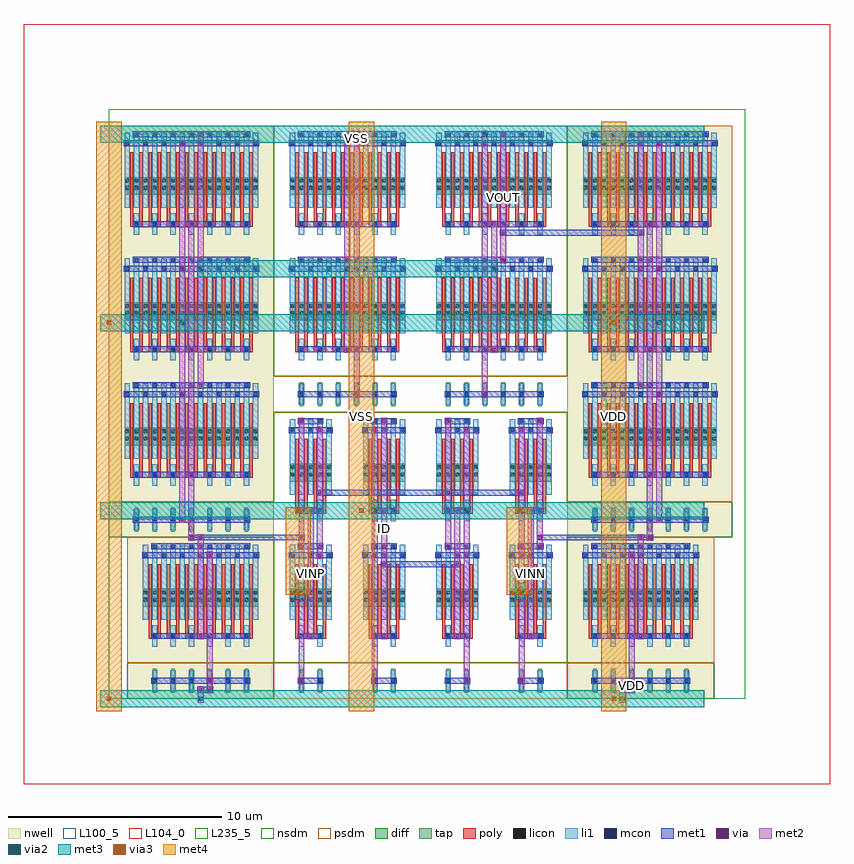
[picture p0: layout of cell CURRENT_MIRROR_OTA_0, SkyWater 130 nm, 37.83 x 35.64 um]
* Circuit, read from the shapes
.subckt CURRENT_MIRROR_OTA_0 ID VDD VINN VINP VOUT VSS
XM1 n1 VINP n2 VSS sky130_fd_pr__nfet_01v8 w=0.84 l=0.15 m=8
XM2 n3 n3 VSS VSS sky130_fd_pr__nfet_01v8 w=0.84 l=0.15 m=24
XM3 ID ID VSS VSS sky130_fd_pr__nfet_01v8 w=0.84 l=0.15 m=8
XM4 n2 ID VSS VSS sky130_fd_pr__nfet_01v8 w=0.84 l=0.15 m=8
XM5 VOUT n3 VSS VSS sky130_fd_pr__nfet_01v8 w=0.84 l=0.15 m=24
XM6 n4 VINN n2 VSS sky130_fd_pr__nfet_01v8 w=0.84 l=0.15 m=8
XM7 n3 n1 VDD VDD sky130_fd_pr__pfet_01v8 w=0.84 l=0.15 m=42
XM8 n1 n1 VDD VDD sky130_fd_pr__pfet_01v8 w=0.84 l=0.15 m=12
XM9 n4 n4 VDD VDD sky130_fd_pr__pfet_01v8 w=0.84 l=0.15 m=12
XM10 VOUT n4 VDD VDD sky130_fd_pr__pfet_01v8 w=0.84 l=0.15 m=42
.ends

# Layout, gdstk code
from math import pi, radians
import gdstk
lib = gdstk.Library(unit=1e-6, precision=1e-09)
def R(c, l, rs):  # rectangles x0, y0, x1, y1
    for r in rs: c.add(gdstk.rectangle(r[:2], r[2:], *l))
def A(c, l, x, y, w, h, nx, ny, dx, dy):  # array of equal rectangles
    R(c, l, [(x+i*dx, y+j*dy, x+i*dx+w, y+j*dy+h) for i in range(nx) for j in range(ny)])
def P(c, l, *ps):  # polygons
    for p in ps: c.add(gdstk.Polygon(p, *l))
nwell = (64, 20)
diff = (65, 20)
tap = (65, 44)
poly = (66, 20)
licon = (66, 44)
li1 = (67, 20)
mcon = (67, 44)
met1 = (68, 20)
via = (68, 44)
met2 = (69, 20)
via2 = (69, 44)
met3 = (70, 20)
via3 = (70, 44)
met4 = (71, 20)
nsdm = (93, 44)
psdm = (94, 20)
L100_5 = (100, 5)
L104_0 = (104, 0)
L235_5 = (235, 5)

dcl_nmos_s_47956387_x2_y = lib.new_cell('DCL_NMOS_S_47956387_X2_Y2_1725381638')
R(dcl_nmos_s_47956387_x2_y, diff, [(0.735,2.415,2.705,3.255), (0.735,8.295,2.705,9.135)])
R(dcl_nmos_s_47956387_x2_y, tap, [(1.205,12.04,1.375,13.16), (2.065,12.04,2.235,13.16)])
A(dcl_nmos_s_47956387_x2_y, poly, 1, 1.26, 0.15, 3.36, 4, 2, 0.43, 5.88)
R(dcl_nmos_s_47956387_x2_y, poly, [(1,4.485,1.58,4.755), (1.86,4.485,2.44,4.755), (1,10.365,1.58,10.635), (1.86,10.365,2.44,10.635)])
A(dcl_nmos_s_47956387_x2_y, licon, 0.775, 2.495, 0.17, 0.17, 3, 2, 0.43, 0.34)
A(dcl_nmos_s_47956387_x2_y, licon, 1.635, 2.495, 0.17, 0.17, 3, 2, 0.43, 0.34)
A(dcl_nmos_s_47956387_x2_y, licon, 0.775, 8.375, 0.17, 0.17, 3, 2, 0.43, 0.34)
A(dcl_nmos_s_47956387_x2_y, licon, 1.635, 8.375, 0.17, 0.17, 3, 2, 0.43, 0.34)
R(dcl_nmos_s_47956387_x2_y, licon, [(1.205,4.535,1.375,4.705), (2.065,4.535,2.235,4.705), (1.205,10.415,1.375,10.585), (2.065,10.415,2.235,10.585), (1.205,12.515,1.375,12.685), (1.205,12.515,1.375,12.685), (2.065,12.515,2.235,12.685), (2.065,12.515,2.235,12.685)])
A(dcl_nmos_s_47956387_x2_y, li1, 0.735, 0.335, 0.25, 3.53, 5, 2, 0.43, 5.88)
R(dcl_nmos_s_47956387_x2_y, li1, [(1.165,4.115,1.415,5.125), (2.025,4.115,2.275,5.125), (1.165,9.995,1.415,11.005), (2.025,9.995,2.275,11.005), (1.165,12.095,1.415,13.105), (2.025,12.095,2.275,13.105)])
A(dcl_nmos_s_47956387_x2_y, mcon, 0.775, 0.755, 0.17, 0.17, 3, 2, 0.86, 5.88)
R(dcl_nmos_s_47956387_x2_y, mcon, [(1.205,0.335,1.375,0.505), (2.065,0.335,2.235,0.505), (1.205,4.535,1.375,4.705), (2.065,4.535,2.235,4.705), (1.205,6.215,1.375,6.385), (2.065,6.215,2.235,6.385), (1.205,10.415,1.375,10.585), (2.065,10.415,2.235,10.585), (1.205,12.515,1.375,12.685), (2.065,12.515,2.235,12.685)])
R(dcl_nmos_s_47956387_x2_y, met1, [(1.12,0.28,2.32,0.56), (0.69,0.7,2.75,0.98), (1.12,4.48,2.32,4.76), (1.12,6.16,2.32,6.44), (0.69,6.58,2.75,6.86), (1.12,10.36,2.32,10.64), (1.12,12.46,2.32,12.74)])
A(dcl_nmos_s_47956387_x2_y, via, 2.075, 0.765, 0.15, 0.15, 1, 3, 0, 5.88)
R(dcl_nmos_s_47956387_x2_y, via, [(1.645,0.345,1.795,0.495), (1.645,4.545,1.795,4.695), (1.645,6.225,1.795,6.375), (1.645,10.425,1.795,10.575)])
R(dcl_nmos_s_47956387_x2_y, met2, [(1.58,0.26,1.86,10.66), (2.01,0.68,2.29,12.76)])
R(dcl_nmos_s_47956387_x2_y, nsdm, [(0,0,3.44,11.76)])
R(dcl_nmos_s_47956387_x2_y, psdm, [(0,11.76,3.44,13.44)])
R(dcl_nmos_s_47956387_x2_y, L100_5, [(0,0,3.44,13.44)])

dcl_nmos_s_13341824_x6_y = lib.new_cell('DCL_NMOS_S_13341824_X6_Y2_1725381637')
R(dcl_nmos_s_13341824_x6_y, diff, [(0.735,2.415,6.145,3.255), (0.735,8.295,6.145,9.135)])
A(dcl_nmos_s_13341824_x6_y, tap, 1.205, 12.04, 0.17, 1.12, 6, 1, 0.86, 0)
A(dcl_nmos_s_13341824_x6_y, poly, 1, 1.26, 0.15, 3.36, 12, 2, 0.43, 5.88)
A(dcl_nmos_s_13341824_x6_y, poly, 1, 4.485, 0.58, 0.27, 6, 2, 0.86, 5.88)
A(dcl_nmos_s_13341824_x6_y, licon, 0.775, 2.495, 0.17, 0.17, 3, 2, 0.43, 0.34)
A(dcl_nmos_s_13341824_x6_y, licon, 1.635, 2.495, 0.17, 0.17, 3, 2, 0.43, 0.34)
A(dcl_nmos_s_13341824_x6_y, licon, 2.495, 2.495, 0.17, 0.17, 3, 2, 0.43, 0.34)
A(dcl_nmos_s_13341824_x6_y, licon, 3.355, 2.495, 0.17, 0.17, 3, 2, 0.43, 0.34)
A(dcl_nmos_s_13341824_x6_y, licon, 4.215, 2.495, 0.17, 0.17, 3, 2, 0.43, 0.34)
A(dcl_nmos_s_13341824_x6_y, licon, 5.075, 2.495, 0.17, 0.17, 3, 2, 0.43, 0.34)
A(dcl_nmos_s_13341824_x6_y, licon, 1.205, 4.535, 0.17, 0.17, 6, 2, 0.86, 5.88)
A(dcl_nmos_s_13341824_x6_y, licon, 0.775, 8.375, 0.17, 0.17, 3, 2, 0.43, 0.34)
A(dcl_nmos_s_13341824_x6_y, licon, 1.635, 8.375, 0.17, 0.17, 3, 2, 0.43, 0.34)
A(dcl_nmos_s_13341824_x6_y, licon, 2.495, 8.375, 0.17, 0.17, 3, 2, 0.43, 0.34)
A(dcl_nmos_s_13341824_x6_y, licon, 3.355, 8.375, 0.17, 0.17, 3, 2, 0.43, 0.34)
A(dcl_nmos_s_13341824_x6_y, licon, 4.215, 8.375, 0.17, 0.17, 3, 2, 0.43, 0.34)
A(dcl_nmos_s_13341824_x6_y, licon, 5.075, 8.375, 0.17, 0.17, 3, 2, 0.43, 0.34)
R(dcl_nmos_s_13341824_x6_y, licon, [(1.205,12.515,1.375,12.685), (1.205,12.515,1.375,12.685), (2.065,12.515,2.235,12.685), (2.065,12.515,2.235,12.685), (2.925,12.515,3.095,12.685), (2.925,12.515,3.095,12.685), (3.785,12.515,3.955,12.685), (3.785,12.515,3.955,12.685), (4.645,12.515,4.815,12.685), (4.645,12.515,4.815,12.685), (5.505,12.515,5.675,12.685), (5.505,12.515,5.675,12.685)])
A(dcl_nmos_s_13341824_x6_y, li1, 0.735, 0.335, 0.25, 3.53, 13, 2, 0.43, 5.88)
A(dcl_nmos_s_13341824_x6_y, li1, 1.165, 4.115, 0.25, 1.01, 6, 2, 0.86, 5.88)
A(dcl_nmos_s_13341824_x6_y, li1, 1.165, 12.095, 0.25, 1.01, 6, 1, 0.86, 0)
A(dcl_nmos_s_13341824_x6_y, mcon, 1.205, 0.335, 0.17, 0.17, 6, 2, 0.86, 4.2)
A(dcl_nmos_s_13341824_x6_y, mcon, 0.775, 0.755, 0.17, 0.17, 7, 2, 0.86, 5.88)
A(dcl_nmos_s_13341824_x6_y, mcon, 1.205, 6.215, 0.17, 0.17, 6, 2, 0.86, 4.2)
A(dcl_nmos_s_13341824_x6_y, mcon, 1.205, 12.515, 0.17, 0.17, 6, 1, 0.86, 0)
R(dcl_nmos_s_13341824_x6_y, met1, [(1.12,0.28,5.76,0.56), (0.69,0.7,6.19,0.98), (1.12,4.48,5.76,4.76), (1.12,6.16,5.76,6.44), (0.69,6.58,6.19,6.86), (1.12,10.36,5.76,10.64), (1.12,12.46,5.76,12.74)])
A(dcl_nmos_s_13341824_x6_y, via, 3.795, 0.765, 0.15, 0.15, 1, 3, 0, 5.88)
R(dcl_nmos_s_13341824_x6_y, via, [(3.365,0.345,3.515,0.495), (3.365,4.545,3.515,4.695), (3.365,6.225,3.515,6.375), (3.365,10.425,3.515,10.575)])
R(dcl_nmos_s_13341824_x6_y, met2, [(3.3,0.26,3.58,10.66), (3.73,0.68,4.01,12.76)])
R(dcl_nmos_s_13341824_x6_y, nsdm, [(0,0,6.88,11.76)])
R(dcl_nmos_s_13341824_x6_y, psdm, [(0,11.76,6.88,13.44)])
R(dcl_nmos_s_13341824_x6_y, L100_5, [(0,0,6.88,13.44)])

dcl_pmos_s_40212493_x6_y = lib.new_cell('DCL_PMOS_S_40212493_X6_Y1_1725381639')
R(dcl_pmos_s_40212493_x6_y, nwell, [(0,0,6.88,7.56)])
R(dcl_pmos_s_40212493_x6_y, diff, [(0.735,2.415,6.145,3.255)])
A(dcl_pmos_s_40212493_x6_y, tap, 1.205, 6.16, 0.17, 1.12, 6, 1, 0.86, 0)
A(dcl_pmos_s_40212493_x6_y, poly, 1, 1.26, 0.15, 3.36, 12, 1, 0.43, 0)
A(dcl_pmos_s_40212493_x6_y, poly, 1, 4.485, 0.58, 0.27, 6, 1, 0.86, 0)
A(dcl_pmos_s_40212493_x6_y, licon, 0.775, 2.495, 0.17, 0.17, 3, 2, 0.43, 0.34)
A(dcl_pmos_s_40212493_x6_y, licon, 1.635, 2.495, 0.17, 0.17, 3, 2, 0.43, 0.34)
A(dcl_pmos_s_40212493_x6_y, licon, 2.495, 2.495, 0.17, 0.17, 3, 2, 0.43, 0.34)
A(dcl_pmos_s_40212493_x6_y, licon, 3.355, 2.495, 0.17, 0.17, 3, 2, 0.43, 0.34)
A(dcl_pmos_s_40212493_x6_y, licon, 4.215, 2.495, 0.17, 0.17, 3, 2, 0.43, 0.34)
A(dcl_pmos_s_40212493_x6_y, licon, 5.075, 2.495, 0.17, 0.17, 3, 2, 0.43, 0.34)
A(dcl_pmos_s_40212493_x6_y, licon, 1.205, 4.535, 0.17, 0.17, 6, 2, 0.86, 2.1)
A(dcl_pmos_s_40212493_x6_y, li1, 0.735, 0.335, 0.25, 3.53, 13, 1, 0.43, 0)
A(dcl_pmos_s_40212493_x6_y, li1, 1.165, 4.115, 0.25, 1.01, 6, 2, 0.86, 2.1)
A(dcl_pmos_s_40212493_x6_y, mcon, 1.205, 0.335, 0.17, 0.17, 6, 2, 0.86, 4.2)
A(dcl_pmos_s_40212493_x6_y, mcon, 0.775, 0.755, 0.17, 0.17, 7, 1, 0.86, 0)
A(dcl_pmos_s_40212493_x6_y, mcon, 1.205, 6.635, 0.17, 0.17, 6, 1, 0.86, 0)
R(dcl_pmos_s_40212493_x6_y, met1, [(1.12,0.28,5.76,0.56), (0.69,0.7,6.19,0.98), (1.12,4.48,5.76,4.76), (1.12,6.58,5.76,6.86)])
R(dcl_pmos_s_40212493_x6_y, via, [(3.365,0.345,3.515,0.495), (3.795,0.765,3.945,0.915), (3.365,4.545,3.515,4.695), (3.795,6.645,3.945,6.795)])
R(dcl_pmos_s_40212493_x6_y, met2, [(3.3,0.26,3.58,4.78), (3.73,0.68,4.01,6.88)])
R(dcl_pmos_s_40212493_x6_y, nsdm, [(0,5.88,6.88,7.56)])
R(dcl_pmos_s_40212493_x6_y, psdm, [(0,0,6.88,5.88)])
R(dcl_pmos_s_40212493_x6_y, L100_5, [(0,0,6.88,7.56)])

nmos_s_7151189_x6_y2_172 = lib.new_cell('NMOS_S_7151189_X6_Y2_1725381642')
R(nmos_s_7151189_x6_y2_172, diff, [(0.735,2.415,6.145,3.255), (0.735,8.295,6.145,9.135)])
A(nmos_s_7151189_x6_y2_172, tap, 1.205, 12.04, 0.17, 1.12, 6, 1, 0.86, 0)
A(nmos_s_7151189_x6_y2_172, poly, 1, 1.26, 0.15, 3.36, 12, 2, 0.43, 5.88)
A(nmos_s_7151189_x6_y2_172, poly, 1, 4.485, 0.58, 0.27, 6, 2, 0.86, 5.88)
A(nmos_s_7151189_x6_y2_172, licon, 0.775, 2.495, 0.17, 0.17, 3, 2, 0.43, 0.34)
A(nmos_s_7151189_x6_y2_172, licon, 1.635, 2.495, 0.17, 0.17, 3, 2, 0.43, 0.34)
A(nmos_s_7151189_x6_y2_172, licon, 2.495, 2.495, 0.17, 0.17, 3, 2, 0.43, 0.34)
A(nmos_s_7151189_x6_y2_172, licon, 3.355, 2.495, 0.17, 0.17, 3, 2, 0.43, 0.34)
A(nmos_s_7151189_x6_y2_172, licon, 4.215, 2.495, 0.17, 0.17, 3, 2, 0.43, 0.34)
A(nmos_s_7151189_x6_y2_172, licon, 5.075, 2.495, 0.17, 0.17, 3, 2, 0.43, 0.34)
A(nmos_s_7151189_x6_y2_172, licon, 1.205, 4.535, 0.17, 0.17, 6, 2, 0.86, 5.88)
A(nmos_s_7151189_x6_y2_172, licon, 0.775, 8.375, 0.17, 0.17, 3, 2, 0.43, 0.34)
A(nmos_s_7151189_x6_y2_172, licon, 1.635, 8.375, 0.17, 0.17, 3, 2, 0.43, 0.34)
A(nmos_s_7151189_x6_y2_172, licon, 2.495, 8.375, 0.17, 0.17, 3, 2, 0.43, 0.34)
A(nmos_s_7151189_x6_y2_172, licon, 3.355, 8.375, 0.17, 0.17, 3, 2, 0.43, 0.34)
A(nmos_s_7151189_x6_y2_172, licon, 4.215, 8.375, 0.17, 0.17, 3, 2, 0.43, 0.34)
A(nmos_s_7151189_x6_y2_172, licon, 5.075, 8.375, 0.17, 0.17, 3, 2, 0.43, 0.34)
R(nmos_s_7151189_x6_y2_172, licon, [(1.205,12.515,1.375,12.685), (1.205,12.515,1.375,12.685), (2.065,12.515,2.235,12.685), (2.065,12.515,2.235,12.685), (2.925,12.515,3.095,12.685), (2.925,12.515,3.095,12.685), (3.785,12.515,3.955,12.685), (3.785,12.515,3.955,12.685), (4.645,12.515,4.815,12.685), (4.645,12.515,4.815,12.685), (5.505,12.515,5.675,12.685), (5.505,12.515,5.675,12.685)])
A(nmos_s_7151189_x6_y2_172, li1, 0.735, 0.335, 0.25, 3.53, 13, 2, 0.43, 5.88)
A(nmos_s_7151189_x6_y2_172, li1, 1.165, 4.115, 0.25, 1.01, 6, 2, 0.86, 5.88)
A(nmos_s_7151189_x6_y2_172, li1, 1.165, 12.095, 0.25, 1.01, 6, 1, 0.86, 0)
A(nmos_s_7151189_x6_y2_172, mcon, 1.205, 0.335, 0.17, 0.17, 6, 2, 0.86, 4.2)
A(nmos_s_7151189_x6_y2_172, mcon, 0.775, 0.755, 0.17, 0.17, 7, 2, 0.86, 5.88)
A(nmos_s_7151189_x6_y2_172, mcon, 1.205, 6.215, 0.17, 0.17, 6, 2, 0.86, 4.2)
A(nmos_s_7151189_x6_y2_172, mcon, 1.205, 12.515, 0.17, 0.17, 6, 1, 0.86, 0)
R(nmos_s_7151189_x6_y2_172, met1, [(1.12,0.28,5.76,0.56), (0.69,0.7,6.19,0.98), (1.12,4.48,5.76,4.76), (1.12,6.16,5.76,6.44), (0.69,6.58,6.19,6.86), (1.12,10.36,5.76,10.64), (1.12,12.46,5.76,12.74)])
A(nmos_s_7151189_x6_y2_172, via, 3.795, 0.765, 0.15, 0.15, 1, 3, 0, 5.88)
R(nmos_s_7151189_x6_y2_172, via, [(2.935,0.345,3.085,0.495), (3.365,4.545,3.515,4.695), (2.935,6.225,3.085,6.375), (3.365,10.425,3.515,10.575)])
R(nmos_s_7151189_x6_y2_172, met2, [(2.87,0.26,3.15,6.46), (3.73,0.68,4.01,12.76), (3.3,4.46,3.58,10.66)])
R(nmos_s_7151189_x6_y2_172, nsdm, [(0,0,6.88,11.76)])
R(nmos_s_7151189_x6_y2_172, psdm, [(0,11.76,6.88,13.44)])
R(nmos_s_7151189_x6_y2_172, L100_5, [(0,0,6.88,13.44)])

nmos_s_18635307_x2_y2_17 = lib.new_cell('NMOS_S_18635307_X2_Y2_1725381641')
R(nmos_s_18635307_x2_y2_17, diff, [(0.735,2.415,2.705,3.255), (0.735,8.295,2.705,9.135)])
R(nmos_s_18635307_x2_y2_17, tap, [(1.205,12.04,1.375,13.16), (2.065,12.04,2.235,13.16)])
A(nmos_s_18635307_x2_y2_17, poly, 1, 1.26, 0.15, 3.36, 4, 2, 0.43, 5.88)
R(nmos_s_18635307_x2_y2_17, poly, [(1,4.485,1.58,4.755), (1.86,4.485,2.44,4.755), (1,10.365,1.58,10.635), (1.86,10.365,2.44,10.635)])
A(nmos_s_18635307_x2_y2_17, licon, 0.775, 2.495, 0.17, 0.17, 3, 2, 0.43, 0.34)
A(nmos_s_18635307_x2_y2_17, licon, 1.635, 2.495, 0.17, 0.17, 3, 2, 0.43, 0.34)
A(nmos_s_18635307_x2_y2_17, licon, 0.775, 8.375, 0.17, 0.17, 3, 2, 0.43, 0.34)
A(nmos_s_18635307_x2_y2_17, licon, 1.635, 8.375, 0.17, 0.17, 3, 2, 0.43, 0.34)
R(nmos_s_18635307_x2_y2_17, licon, [(1.205,4.535,1.375,4.705), (2.065,4.535,2.235,4.705), (1.205,10.415,1.375,10.585), (2.065,10.415,2.235,10.585), (1.205,12.515,1.375,12.685), (1.205,12.515,1.375,12.685), (2.065,12.515,2.235,12.685), (2.065,12.515,2.235,12.685)])
A(nmos_s_18635307_x2_y2_17, li1, 0.735, 0.335, 0.25, 3.53, 5, 2, 0.43, 5.88)
R(nmos_s_18635307_x2_y2_17, li1, [(1.165,4.115,1.415,5.125), (2.025,4.115,2.275,5.125), (1.165,9.995,1.415,11.005), (2.025,9.995,2.275,11.005), (1.165,12.095,1.415,13.105), (2.025,12.095,2.275,13.105)])
A(nmos_s_18635307_x2_y2_17, mcon, 0.775, 0.755, 0.17, 0.17, 3, 2, 0.86, 5.88)
R(nmos_s_18635307_x2_y2_17, mcon, [(1.205,0.335,1.375,0.505), (2.065,0.335,2.235,0.505), (1.205,4.535,1.375,4.705), (2.065,4.535,2.235,4.705), (1.205,6.215,1.375,6.385), (2.065,6.215,2.235,6.385), (1.205,10.415,1.375,10.585), (2.065,10.415,2.235,10.585), (1.205,12.515,1.375,12.685), (2.065,12.515,2.235,12.685)])
R(nmos_s_18635307_x2_y2_17, met1, [(1.12,0.28,2.32,0.56), (0.69,0.7,2.75,0.98), (1.12,4.48,2.32,4.76), (1.12,6.16,2.32,6.44), (0.69,6.58,2.75,6.86), (1.12,10.36,2.32,10.64), (1.12,12.46,2.32,12.74)])
A(nmos_s_18635307_x2_y2_17, via, 2.075, 0.765, 0.15, 0.15, 1, 3, 0, 5.88)
R(nmos_s_18635307_x2_y2_17, via, [(1.215,0.345,1.365,0.495), (1.645,4.545,1.795,4.695), (1.215,6.225,1.365,6.375), (1.645,10.425,1.795,10.575)])
R(nmos_s_18635307_x2_y2_17, met2, [(1.15,0.26,1.43,6.46), (2.01,0.68,2.29,12.76), (1.58,4.46,1.86,10.66)])
R(nmos_s_18635307_x2_y2_17, nsdm, [(0,0,3.44,11.76)])
R(nmos_s_18635307_x2_y2_17, psdm, [(0,11.76,3.44,13.44)])
R(nmos_s_18635307_x2_y2_17, L100_5, [(0,0,3.44,13.44)])

pmos_s_18257507_x7_y3_17 = lib.new_cell('PMOS_S_18257507_X7_Y3_1725381643')
R(pmos_s_18257507_x7_y3_17, nwell, [(0,0,7.74,19.32)])
A(pmos_s_18257507_x7_y3_17, diff, 0.735, 2.415, 6.27, 0.84, 1, 3, 0, 5.88)
A(pmos_s_18257507_x7_y3_17, tap, 1.205, 17.92, 0.17, 1.12, 7, 1, 0.86, 0)
A(pmos_s_18257507_x7_y3_17, poly, 1, 1.26, 0.15, 3.36, 14, 3, 0.43, 5.88)
A(pmos_s_18257507_x7_y3_17, poly, 1, 4.485, 0.58, 0.27, 7, 3, 0.86, 5.88)
A(pmos_s_18257507_x7_y3_17, licon, 0.775, 2.495, 0.17, 0.17, 3, 2, 0.43, 0.34)
A(pmos_s_18257507_x7_y3_17, licon, 1.635, 2.495, 0.17, 0.17, 3, 2, 0.43, 0.34)
A(pmos_s_18257507_x7_y3_17, licon, 2.495, 2.495, 0.17, 0.17, 3, 2, 0.43, 0.34)
A(pmos_s_18257507_x7_y3_17, licon, 3.355, 2.495, 0.17, 0.17, 3, 2, 0.43, 0.34)
A(pmos_s_18257507_x7_y3_17, licon, 4.215, 2.495, 0.17, 0.17, 3, 2, 0.43, 0.34)
A(pmos_s_18257507_x7_y3_17, licon, 5.075, 2.495, 0.17, 0.17, 3, 2, 0.43, 0.34)
A(pmos_s_18257507_x7_y3_17, licon, 5.935, 2.495, 0.17, 0.17, 3, 2, 0.43, 0.34)
A(pmos_s_18257507_x7_y3_17, licon, 1.205, 4.535, 0.17, 0.17, 7, 3, 0.86, 5.88)
A(pmos_s_18257507_x7_y3_17, licon, 0.775, 8.375, 0.17, 0.17, 3, 2, 0.43, 0.34)
A(pmos_s_18257507_x7_y3_17, licon, 1.635, 8.375, 0.17, 0.17, 3, 2, 0.43, 0.34)
A(pmos_s_18257507_x7_y3_17, licon, 2.495, 8.375, 0.17, 0.17, 3, 2, 0.43, 0.34)
A(pmos_s_18257507_x7_y3_17, licon, 3.355, 8.375, 0.17, 0.17, 3, 2, 0.43, 0.34)
A(pmos_s_18257507_x7_y3_17, licon, 4.215, 8.375, 0.17, 0.17, 3, 2, 0.43, 0.34)
A(pmos_s_18257507_x7_y3_17, licon, 5.075, 8.375, 0.17, 0.17, 3, 2, 0.43, 0.34)
A(pmos_s_18257507_x7_y3_17, licon, 5.935, 8.375, 0.17, 0.17, 3, 2, 0.43, 0.34)
A(pmos_s_18257507_x7_y3_17, licon, 0.775, 14.255, 0.17, 0.17, 3, 2, 0.43, 0.34)
A(pmos_s_18257507_x7_y3_17, licon, 1.635, 14.255, 0.17, 0.17, 3, 2, 0.43, 0.34)
A(pmos_s_18257507_x7_y3_17, licon, 2.495, 14.255, 0.17, 0.17, 3, 2, 0.43, 0.34)
A(pmos_s_18257507_x7_y3_17, licon, 3.355, 14.255, 0.17, 0.17, 3, 2, 0.43, 0.34)
A(pmos_s_18257507_x7_y3_17, licon, 4.215, 14.255, 0.17, 0.17, 3, 2, 0.43, 0.34)
A(pmos_s_18257507_x7_y3_17, licon, 5.075, 14.255, 0.17, 0.17, 3, 2, 0.43, 0.34)
A(pmos_s_18257507_x7_y3_17, licon, 5.935, 14.255, 0.17, 0.17, 3, 2, 0.43, 0.34)
R(pmos_s_18257507_x7_y3_17, licon, [(1.205,18.395,1.375,18.565), (1.205,18.395,1.375,18.565), (1.205,18.395,1.375,18.565), (2.065,18.395,2.235,18.565), (2.065,18.395,2.235,18.565), (2.065,18.395,2.235,18.565), (2.925,18.395,3.095,18.565), (2.925,18.395,3.095,18.565), (2.925,18.395,3.095,18.565), (3.785,18.395,3.955,18.565), (3.785,18.395,3.955,18.565), (3.785,18.395,3.955,18.565), (4.645,18.395,4.815,18.565), (4.645,18.395,4.815,18.565), (4.645,18.395,4.815,18.565), (5.505,18.395,5.675,18.565), (5.505,18.395,5.675,18.565), (5.505,18.395,5.675,18.565), (6.365,18.395,6.535,18.565), (6.365,18.395,6.535,18.565), (6.365,18.395,6.535,18.565)])
A(pmos_s_18257507_x7_y3_17, li1, 0.735, 0.335, 0.25, 3.53, 15, 3, 0.43, 5.88)
A(pmos_s_18257507_x7_y3_17, li1, 1.165, 4.115, 0.25, 1.01, 7, 3, 0.86, 5.88)
A(pmos_s_18257507_x7_y3_17, li1, 1.165, 17.975, 0.25, 1.01, 7, 1, 0.86, 0)
A(pmos_s_18257507_x7_y3_17, mcon, 1.205, 0.335, 0.17, 0.17, 7, 2, 0.86, 4.2)
A(pmos_s_18257507_x7_y3_17, mcon, 0.775, 0.755, 0.17, 0.17, 8, 3, 0.86, 5.88)
A(pmos_s_18257507_x7_y3_17, mcon, 1.205, 6.215, 0.17, 0.17, 7, 2, 0.86, 4.2)
A(pmos_s_18257507_x7_y3_17, mcon, 1.205, 12.095, 0.17, 0.17, 7, 2, 0.86, 4.2)
A(pmos_s_18257507_x7_y3_17, mcon, 1.205, 18.395, 0.17, 0.17, 7, 1, 0.86, 0)
A(pmos_s_18257507_x7_y3_17, met1, 0.69, 0.7, 6.36, 0.28, 1, 3, 0, 5.88)
R(pmos_s_18257507_x7_y3_17, met1, [(1.12,0.28,6.62,0.56), (1.12,4.48,6.62,4.76), (1.12,6.16,6.62,6.44), (1.12,10.36,6.62,10.64), (1.12,12.04,6.62,12.32), (1.12,16.24,6.62,16.52), (1.12,18.34,6.62,18.62)])
A(pmos_s_18257507_x7_y3_17, via, 3.365, 0.345, 0.15, 0.15, 1, 3, 0, 5.88)
A(pmos_s_18257507_x7_y3_17, via, 4.225, 0.765, 0.15, 0.15, 1, 4, 0, 5.88)
A(pmos_s_18257507_x7_y3_17, via, 3.795, 4.545, 0.15, 0.15, 1, 3, 0, 5.88)
R(pmos_s_18257507_x7_y3_17, met2, [(3.3,0.26,3.58,12.34), (4.16,0.68,4.44,18.64), (3.73,4.46,4.01,16.54)])
R(pmos_s_18257507_x7_y3_17, nsdm, [(0,17.64,7.74,19.32)])
R(pmos_s_18257507_x7_y3_17, psdm, [(0,0,7.74,17.64)])
R(pmos_s_18257507_x7_y3_17, L100_5, [(0,0,7.74,19.32)])

nmos_4t_40251920_x2_y2_1 = lib.new_cell('NMOS_4T_40251920_X2_Y2_1725381640')
R(nmos_4t_40251920_x2_y2_1, diff, [(0.735,2.415,2.705,3.255), (0.735,8.295,2.705,9.135)])
R(nmos_4t_40251920_x2_y2_1, tap, [(1.205,12.04,1.375,13.16), (2.065,12.04,2.235,13.16)])
A(nmos_4t_40251920_x2_y2_1, poly, 1, 1.26, 0.15, 3.36, 4, 2, 0.43, 5.88)
R(nmos_4t_40251920_x2_y2_1, poly, [(1,4.485,1.58,4.755), (1.86,4.485,2.44,4.755), (1,10.365,1.58,10.635), (1.86,10.365,2.44,10.635)])
A(nmos_4t_40251920_x2_y2_1, licon, 0.775, 2.495, 0.17, 0.17, 3, 2, 0.43, 0.34)
A(nmos_4t_40251920_x2_y2_1, licon, 1.635, 2.495, 0.17, 0.17, 3, 2, 0.43, 0.34)
A(nmos_4t_40251920_x2_y2_1, licon, 0.775, 8.375, 0.17, 0.17, 3, 2, 0.43, 0.34)
A(nmos_4t_40251920_x2_y2_1, licon, 1.635, 8.375, 0.17, 0.17, 3, 2, 0.43, 0.34)
R(nmos_4t_40251920_x2_y2_1, licon, [(1.205,4.535,1.375,4.705), (2.065,4.535,2.235,4.705), (1.205,10.415,1.375,10.585), (2.065,10.415,2.235,10.585), (1.205,12.515,1.375,12.685), (1.205,12.515,1.375,12.685), (2.065,12.515,2.235,12.685), (2.065,12.515,2.235,12.685)])
A(nmos_4t_40251920_x2_y2_1, li1, 0.735, 0.335, 0.25, 3.53, 5, 2, 0.43, 5.88)
R(nmos_4t_40251920_x2_y2_1, li1, [(1.165,4.115,1.415,5.125), (2.025,4.115,2.275,5.125), (1.165,9.995,1.415,11.005), (2.025,9.995,2.275,11.005), (1.165,12.095,1.415,13.105), (2.025,12.095,2.275,13.105)])
A(nmos_4t_40251920_x2_y2_1, mcon, 0.775, 0.755, 0.17, 0.17, 3, 2, 0.86, 5.88)
R(nmos_4t_40251920_x2_y2_1, mcon, [(1.205,0.335,1.375,0.505), (2.065,0.335,2.235,0.505), (1.205,4.535,1.375,4.705), (2.065,4.535,2.235,4.705), (1.205,6.215,1.375,6.385), (2.065,6.215,2.235,6.385), (1.205,10.415,1.375,10.585), (2.065,10.415,2.235,10.585), (1.205,12.515,1.375,12.685), (2.065,12.515,2.235,12.685)])
R(nmos_4t_40251920_x2_y2_1, met1, [(1.12,0.28,2.32,0.56), (0.69,0.7,2.75,0.98), (1.12,4.48,2.32,4.76), (1.12,6.16,2.32,6.44), (0.69,6.58,2.75,6.86), (1.12,10.36,2.32,10.64), (1.12,12.46,2.32,12.74)])
R(nmos_4t_40251920_x2_y2_1, via, [(1.215,0.345,1.365,0.495), (2.075,0.765,2.225,0.915), (1.645,4.545,1.795,4.695), (1.215,6.225,1.365,6.375), (2.075,6.645,2.225,6.795), (1.645,10.425,1.795,10.575)])
R(nmos_4t_40251920_x2_y2_1, met2, [(1.15,0.26,1.43,6.46), (2.01,0.68,2.29,6.88), (1.58,4.46,1.86,10.66)])
R(nmos_4t_40251920_x2_y2_1, nsdm, [(0,0,3.44,11.76)])
R(nmos_4t_40251920_x2_y2_1, psdm, [(0,11.76,3.44,13.44)])
R(nmos_4t_40251920_x2_y2_1, L100_5, [(0,0,3.44,13.44)])

current_mirror_ota_0 = lib.new_cell('CURRENT_MIRROR_OTA_0')
R(current_mirror_ota_0, met1, [(4.14,0.28,4.46,0.56), (4.14,0.28,4.46,0.56), (4.14,0.28,4.46,0.56), (4.14,0.28,4.46,0.56), (4.3,0.28,4.73,0.56), (4.57,0.28,4.89,0.56), (4.57,0.28,4.89,0.56), (4.57,0.28,4.89,0.56), (4.57,0.28,4.89,0.56), (23.92,0.28,24.24,0.56), (23.92,0.28,24.24,0.56), (23.92,0.28,24.24,0.56), (23.92,0.28,24.24,0.56), (23.92,0.28,24.24,0.56), (24.08,0.28,24.51,0.56), (24.35,0.28,24.67,0.56), (24.35,0.28,24.67,0.56), (24.35,0.28,24.67,0.56), (24.35,0.28,24.67,0.56), (24.35,0.28,24.67,0.56), (8.87,0.7,9.19,0.98), (8.87,0.7,9.19,0.98), (19.19,0.7,19.51,0.98), (19.19,0.7,19.51,0.98), (19.19,0.7,19.51,0.98), (12.74,6.16,13.06,6.44), (12.74,6.16,13.06,6.44), (12.9,6.16,16.34,6.44), (16.18,6.16,16.5,6.44), (16.18,6.16,16.5,6.44), (3.71,7.42,4.03,7.7), (3.71,7.42,4.03,7.7), (3.87,7.42,4.3,7.7), (4.14,7.42,4.46,7.7), (4.14,7.42,4.46,7.7), (4.14,7.42,4.46,7.7), (4.14,7.42,4.46,7.7), (4.3,7.42,9.03,7.7), (8.87,7.42,9.19,7.7), (8.87,7.42,9.19,7.7), (8.87,7.42,9.19,7.7), (8.87,7.42,9.19,7.7), (20.05,7.42,20.37,7.7), (20.05,7.42,20.37,7.7), (20.05,7.42,20.37,7.7), (20.05,7.42,20.37,7.7), (20.21,7.42,24.94,7.7), (24.78,7.42,25.1,7.7), (24.78,7.42,25.1,7.7), (24.78,7.42,25.1,7.7), (24.78,7.42,25.1,7.7), (24.94,7.42,25.37,7.7), (25.21,7.42,25.53,7.7), (25.21,7.42,25.53,7.7), (9.73,9.52,10.05,9.8), (9.73,9.52,10.05,9.8), (9.73,9.52,10.05,9.8), (9.73,9.52,10.05,9.8), (9.89,9.52,15.91,9.8), (15.75,9.52,16.07,9.8), (15.75,9.52,16.07,9.8), (15.75,9.52,16.07,9.8), (15.75,9.52,16.07,9.8), (15.91,9.52,19.35,9.8), (19.19,9.52,19.51,9.8), (19.19,9.52,19.51,9.8), (18.33,21.7,18.65,21.98), (18.33,21.7,18.65,21.98), (18.49,21.7,24.94,21.98), (24.78,21.7,25.1,21.98), (24.78,21.7,25.1,21.98)])
P(current_mirror_ota_0, met1, [(0,0),(0,0),(0,0),(0,0)],
  [(0,0),(0,0),(0,0),(0,0)])
R(current_mirror_ota_0, via, [(4.225,0.345,4.375,0.495), (4.225,0.345,4.375,0.495), (4.225,0.345,4.375,0.495), (4.225,0.345,4.375,0.495), (4.655,0.345,4.805,0.495), (4.655,0.345,4.805,0.495), (4.655,0.345,4.805,0.495), (4.655,0.345,4.805,0.495), (24.005,0.345,24.155,0.495), (24.005,0.345,24.155,0.495), (24.005,0.345,24.155,0.495), (24.005,0.345,24.155,0.495), (24.005,0.345,24.155,0.495), (24.435,0.345,24.585,0.495), (24.435,0.345,24.585,0.495), (24.435,0.345,24.585,0.495), (24.435,0.345,24.585,0.495), (24.435,0.345,24.585,0.495), (8.955,0.765,9.105,0.915), (8.955,0.765,9.105,0.915), (19.275,0.765,19.425,0.915), (19.275,0.765,19.425,0.915), (19.275,0.765,19.425,0.915), (12.825,6.225,12.975,6.375), (12.825,6.225,12.975,6.375), (16.265,6.225,16.415,6.375), (16.265,6.225,16.415,6.375), (3.795,7.485,3.945,7.635), (3.795,7.485,3.945,7.635), (4.225,7.485,4.375,7.635), (4.225,7.485,4.375,7.635), (4.225,7.485,4.375,7.635), (4.225,7.485,4.375,7.635), (8.955,7.485,9.105,7.635), (8.955,7.485,9.105,7.635), (8.955,7.485,9.105,7.635), (8.955,7.485,9.105,7.635), (20.135,7.485,20.285,7.635), (20.135,7.485,20.285,7.635), (20.135,7.485,20.285,7.635), (20.135,7.485,20.285,7.635), (24.865,7.485,25.015,7.635), (24.865,7.485,25.015,7.635), (24.865,7.485,25.015,7.635), (24.865,7.485,25.015,7.635), (25.295,7.485,25.445,7.635), (25.295,7.485,25.445,7.635), (9.815,9.585,9.965,9.735), (9.815,9.585,9.965,9.735), (9.815,9.585,9.965,9.735), (9.815,9.585,9.965,9.735), (15.835,9.585,15.985,9.735), (15.835,9.585,15.985,9.735), (15.835,9.585,15.985,9.735), (15.835,9.585,15.985,9.735), (19.275,9.585,19.425,9.735), (19.275,9.585,19.425,9.735), (18.415,21.765,18.565,21.915), (18.415,21.765,18.565,21.915), (24.865,21.765,25.015,21.915), (24.865,21.765,25.015,21.915)])
R(current_mirror_ota_0, met2, [(4.16,-0.185,4.44,0.185), (4.16,-0.185,4.44,0.185), (4.16,-0.185,4.44,0.185), (4.16,-0.185,4.44,0.185), (23.94,-0.185,24.22,0.185), (23.94,-0.185,24.22,0.185), (23.94,-0.185,24.22,0.185), (23.94,-0.185,24.22,0.185), (23.94,-0.185,24.22,0.185), (4.16,0,4.44,0.42), (23.94,0,24.22,0.42), (4.16,0.26,4.44,0.58), (4.16,0.26,4.44,0.58), (4.16,0.26,4.44,0.58), (4.16,0.26,4.44,0.58), (4.59,0.26,4.87,0.58), (4.59,0.26,4.87,0.58), (4.59,0.26,4.87,0.58), (4.59,0.26,4.87,0.58), (23.94,0.26,24.22,0.58), (23.94,0.26,24.22,0.58), (23.94,0.26,24.22,0.58), (23.94,0.26,24.22,0.58), (23.94,0.26,24.22,0.58), (24.37,0.26,24.65,0.58), (24.37,0.26,24.65,0.58), (24.37,0.26,24.65,0.58), (24.37,0.26,24.65,0.58), (24.37,0.26,24.65,0.58), (4.59,0.42,4.87,0.84), (24.37,0.42,24.65,0.84), (8.89,0.68,9.17,1), (8.89,0.68,9.17,1), (19.21,0.68,19.49,1), (19.21,0.68,19.49,1), (19.21,0.68,19.49,1), (8.89,0.84,9.17,5.04), (19.21,0.84,19.49,5.04), (8.89,4.855,9.17,5.225), (19.21,4.855,19.49,5.225), (12.76,6.14,13.04,6.46), (12.76,6.14,13.04,6.46), (16.2,6.14,16.48,6.46), (16.2,6.14,16.48,6.46), (4.16,7.14,4.44,7.56), (24.8,7.14,25.08,7.56), (3.73,7.4,4.01,7.72), (3.73,7.4,4.01,7.72), (4.16,7.4,4.44,7.72), (4.16,7.4,4.44,7.72), (4.16,7.4,4.44,7.72), (4.16,7.4,4.44,7.72), (8.89,7.4,9.17,7.72), (8.89,7.4,9.17,7.72), (8.89,7.4,9.17,7.72), (8.89,7.4,9.17,7.72), (20.07,7.4,20.35,7.72), (20.07,7.4,20.35,7.72), (20.07,7.4,20.35,7.72), (20.07,7.4,20.35,7.72), (24.8,7.4,25.08,7.72), (24.8,7.4,25.08,7.72), (24.8,7.4,25.08,7.72), (24.8,7.4,25.08,7.72), (25.23,7.4,25.51,7.72), (25.23,7.4,25.51,7.72), (3.73,7.56,4.01,10.5), (25.23,7.56,25.51,10.5), (12.33,8.635,12.61,9.005), (12.33,8.635,12.61,9.005), (12.33,8.635,12.61,9.005), (12.33,8.635,12.61,9.005), (12.33,8.635,12.61,9.005), (12.33,8.635,12.61,9.005), (12.33,8.635,12.61,9.005), (16.63,8.635,16.91,9.005), (16.63,8.635,16.91,9.005), (16.63,8.635,16.91,9.005), (16.63,8.635,16.91,9.005), (9.75,9.5,10.03,9.82), (9.75,9.5,10.03,9.82), (9.75,9.5,10.03,9.82), (9.75,9.5,10.03,9.82), (15.77,9.5,16.05,9.82), (15.77,9.5,16.05,9.82), (15.77,9.5,16.05,9.82), (15.77,9.5,16.05,9.82), (19.21,9.5,19.49,9.82), (19.21,9.5,19.49,9.82), (3.3,17.455,3.58,17.825), (3.3,17.455,3.58,17.825), (3.3,17.455,3.58,17.825), (25.66,17.455,25.94,17.825), (25.66,17.455,25.94,17.825), (4.16,19.975,4.44,20.345), (4.16,19.975,4.44,20.345), (4.16,19.975,4.44,20.345), (4.16,19.975,4.44,20.345), (11.04,19.975,11.32,20.345), (11.04,19.975,11.32,20.345), (11.04,19.975,11.32,20.345), (11.04,19.975,11.32,20.345), (17.92,19.975,18.2,20.345), (17.92,19.975,18.2,20.345), (18.35,21.68,18.63,22), (18.35,21.68,18.63,22), (24.8,21.68,25.08,22), (24.8,21.68,25.08,22), (11.47,26.04,11.75,26.46), (17.49,26.04,17.77,26.46), (11.47,26.275,11.75,26.645), (11.47,26.275,11.75,26.645), (11.47,26.275,11.75,26.645), (11.47,26.275,11.75,26.645), (11.47,26.275,11.75,26.645), (11.47,26.275,11.75,26.645), (17.49,26.275,17.77,26.645), (17.49,26.275,17.77,26.645), (17.49,26.275,17.77,26.645), (17.49,26.275,17.77,26.645), (17.49,26.275,17.77,26.645)])
P(current_mirror_ota_0, met2, [(0,0),(0,0),(0,0),(0,0)],
  [(0,0),(0,0),(0,0),(0,0)],
  [(0,0),(0,0),(0,0),(0,0)],
  [(0,0),(0,0),(0,0),(0,0)],
  [(0,0),(0,0),(0,0),(0,0)],
  [(0,0),(0,0),(0,0),(0,0)],
  [(0,0),(0,0),(0,0),(0,0)],
  [(0,0),(0,0),(0,0),(0,0)],
  [(0,0),(0,0),(0,0),(0,0)],
  [(0,0),(0,0),(0,0),(0,0)],
  [(0,0),(0,0),(0,0),(0,0)],
  [(0,0),(0,0),(0,0),(0,0)],
  [(0,0),(0,0),(0,0),(0,0)],
  [(0,0),(0,0),(0,0),(0,0)],
  [(0,0),(0,0),(0,0),(0,0)],
  [(0,0),(0,0),(0,0),(0,0)],
  [(0,0),(0,0),(0,0),(0,0)],
  [(0,0),(0,0),(0,0),(0,0)],
  [(0,0),(0,0),(0,0),(0,0)],
  [(0,0),(0,0),(0,0),(0,0)],
  [(0,0),(0,0),(0,0),(0,0)],
  [(0,0),(0,0),(0,0),(0,0)],
  [(0,0),(0,0),(0,0),(0,0)],
  [(0,0),(0,0),(0,0),(0,0)],
  [(0,0),(0,0),(0,0),(0,0)],
  [(0,0),(0,0),(0,0),(0,0)],
  [(0,0),(0,0),(0,0),(0,0)],
  [(0,0),(0,0),(0,0),(0,0)],
  [(0,0),(0,0),(0,0),(0,0)],
  [(0,0),(0,0),(0,0),(0,0)])
R(current_mirror_ota_0, via2, [(4.2,-0.1,4.4,0.1), (4.2,-0.1,4.4,0.1), (4.2,-0.1,4.4,0.1), (4.2,-0.1,4.4,0.1), (23.98,-0.1,24.18,0.1), (23.98,-0.1,24.18,0.1), (23.98,-0.1,24.18,0.1), (23.98,-0.1,24.18,0.1), (23.98,-0.1,24.18,0.1), (8.93,4.94,9.13,5.14), (19.25,4.94,19.45,5.14), (12.37,8.72,12.57,8.92), (12.37,8.72,12.57,8.92), (12.37,8.72,12.57,8.92), (12.37,8.72,12.57,8.92), (12.37,8.72,12.57,8.92), (12.37,8.72,12.57,8.92), (12.37,8.72,12.57,8.92), (16.67,8.72,16.87,8.92), (16.67,8.72,16.87,8.92), (16.67,8.72,16.87,8.92), (16.67,8.72,16.87,8.92), (3.34,17.54,3.54,17.74), (3.34,17.54,3.54,17.74), (3.34,17.54,3.54,17.74), (25.7,17.54,25.9,17.74), (25.7,17.54,25.9,17.74), (4.2,20.06,4.4,20.26), (4.2,20.06,4.4,20.26), (4.2,20.06,4.4,20.26), (4.2,20.06,4.4,20.26), (11.08,20.06,11.28,20.26), (11.08,20.06,11.28,20.26), (11.08,20.06,11.28,20.26), (11.08,20.06,11.28,20.26), (17.96,20.06,18.16,20.26), (17.96,20.06,18.16,20.26), (11.51,26.36,11.71,26.56), (11.51,26.36,11.71,26.56), (11.51,26.36,11.71,26.56), (11.51,26.36,11.71,26.56), (11.51,26.36,11.71,26.56), (11.51,26.36,11.71,26.56), (17.53,26.36,17.73,26.56), (17.53,26.36,17.73,26.56), (17.53,26.36,17.73,26.56), (17.53,26.36,17.73,26.56), (17.53,26.36,17.73,26.56)])
A(current_mirror_ota_0, met3, -0.4, -0.4, 4.24, 0.8, 3, 4, 3.44, 8.82)
A(current_mirror_ota_0, met3, 9.92, -0.4, 2.32, 0.8, 1, 4, 0, 8.82)
A(current_mirror_ota_0, met3, 11.44, -0.4, 2.72, 0.8, 1, 4, 0, 8.82)
A(current_mirror_ota_0, met3, 13.36, -0.4, 4.24, 0.8, 1, 4, 0, 8.82)
A(current_mirror_ota_0, met3, 16.8, -0.4, 4.24, 0.8, 1, 4, 0, 8.82)
A(current_mirror_ota_0, met3, 20.24, -0.4, 3.84, 0.8, 1, 4, 0, 8.82)
A(current_mirror_ota_0, met3, 23.28, -0.4, 1.2, 0.8, 1, 4, 0, 8.82)
A(current_mirror_ota_0, met3, 23.68, -0.4, 4.24, 0.8, 1, 4, 0, 8.82)
R(current_mirror_ota_0, met3, [(-0.165,-0.4,0.165,0.4), (4.135,-0.4,4.465,0.4), (4.135,-0.4,4.465,0.4), (4.135,-0.4,4.465,0.4), (4.135,-0.4,4.465,0.4), (23.515,-0.4,23.845,0.4), (23.915,-0.4,24.245,0.4), (23.915,-0.4,24.245,0.4), (23.915,-0.4,24.245,0.4), (23.915,-0.4,24.245,0.4), (23.915,-0.4,24.245,0.4), (8.715,4.64,9.045,5.44), (8.805,4.64,9.105,5.44), (8.865,4.64,9.195,5.44), (19.075,4.64,19.405,5.44), (19.145,4.64,19.445,5.44), (19.185,4.64,19.515,5.44), (8.715,8.42,9.045,9.22), (8.715,8.42,9.045,9.22), (11.675,8.42,12.005,9.22), (12.305,8.42,12.635,9.22), (12.305,8.42,12.635,9.22), (12.305,8.42,12.635,9.22), (12.305,8.42,12.635,9.22), (12.305,8.42,12.635,9.22), (12.305,8.42,12.635,9.22), (12.305,8.42,12.635,9.22), (16.605,8.42,16.935,9.22), (16.605,8.42,16.935,9.22), (16.605,8.42,16.935,9.22), (16.605,8.42,16.935,9.22), (19.075,8.42,19.405,9.22), (19.075,8.42,19.405,9.22), (19.075,8.42,19.405,9.22), (-0.165,17.24,0.165,18.04), (3.275,17.24,3.605,18.04), (3.275,17.24,3.605,18.04), (3.275,17.24,3.605,18.04), (23.515,17.24,23.845,18.04), (25.635,17.24,25.965,18.04), (25.635,17.24,25.965,18.04), (4.135,19.76,4.465,20.56), (4.135,19.76,4.465,20.56), (4.135,19.76,4.465,20.56), (4.135,19.76,4.465,20.56), (4.3,19.76,11.18,20.56), (11.015,19.76,11.345,20.56), (11.015,19.76,11.345,20.56), (11.015,19.76,11.345,20.56), (11.015,19.76,11.345,20.56), (11.18,19.76,18.06,20.56), (17.895,19.76,18.225,20.56), (17.895,19.76,18.225,20.56), (11.445,26.06,11.775,26.86), (11.445,26.06,11.775,26.86), (11.445,26.06,11.775,26.86), (11.445,26.06,11.775,26.86), (11.445,26.06,11.775,26.86), (11.445,26.06,11.775,26.86), (11.675,26.06,12.005,26.86), (17.465,26.06,17.795,26.86), (17.465,26.06,17.795,26.86), (17.465,26.06,17.795,26.86), (17.465,26.06,17.795,26.86), (17.465,26.06,17.795,26.86)])
R(current_mirror_ota_0, via3, [(-0.1,-0.1,0.1,0.1), (23.58,-0.1,23.78,0.1), (8.78,4.94,8.98,5.14), (19.14,4.94,19.34,5.14), (8.78,8.72,8.98,8.92), (8.78,8.72,8.98,8.92), (11.74,8.72,11.94,8.92), (19.14,8.72,19.34,8.92), (19.14,8.72,19.34,8.92), (19.14,8.72,19.34,8.92), (-0.1,17.54,0.1,17.74), (23.58,17.54,23.78,17.74), (11.74,26.36,11.94,26.56)])
A(current_mirror_ota_0, met4, -0.59, -0.59, 1.18, 10, 3, 3, 11.84, 8.82)
R(current_mirror_ota_0, met4, [(-0.59,-0.165,0.59,0.165), (23.09,-0.165,24.27,0.165), (8.29,4.875,9.47,5.205), (18.65,4.875,19.83,5.205), (8.29,5.04,9.47,8.82), (18.65,5.04,19.83,8.82), (8.29,8.655,9.47,8.985), (8.29,8.655,9.47,8.985), (11.25,8.655,12.43,8.985), (18.65,8.655,19.83,8.985), (18.65,8.655,19.83,8.985), (18.65,8.655,19.83,8.985), (-0.59,17.475,0.59,17.805), (23.09,17.475,24.27,17.805), (11.25,26.295,12.43,26.625)])
R(current_mirror_ota_0, L104_0, [(-4,-4,33.83,31.64)])
R(current_mirror_ota_0, L235_5, [(0,0,29.83,27.64)])
current_mirror_ota_0.add(gdstk.Reference(dcl_nmos_s_47956387_x2_y, (14.62,13.44), rotation=pi))
current_mirror_ota_0.add(gdstk.Reference(dcl_nmos_s_13341824_x6_y, (7.74,26.88), x_reflection=True))
current_mirror_ota_0.add(gdstk.Reference(dcl_pmos_s_40212493_x6_y, (28.38,7.56), rotation=pi))
current_mirror_ota_0.add(gdstk.Reference(dcl_pmos_s_40212493_x6_y, (0.86,7.56), x_reflection=True))
current_mirror_ota_0.add(gdstk.Reference(nmos_s_7151189_x6_y2_172, (21.5,26.88), rotation=pi))
current_mirror_ota_0.add(gdstk.Reference(nmos_s_18635307_x2_y2_17, (14.62,13.44), x_reflection=True))
current_mirror_ota_0.add(gdstk.Reference(pmos_s_18257507_x7_y3_17, (7.74,26.88), rotation=pi))
current_mirror_ota_0.add(gdstk.Reference(pmos_s_18257507_x7_y3_17, (21.5,26.88), x_reflection=True))
current_mirror_ota_0.add(gdstk.Reference(nmos_4t_40251920_x2_y2_1, (21.5,13.44), rotation=pi))
current_mirror_ota_0.add(gdstk.Reference(nmos_4t_40251920_x2_y2_1, (7.74,13.44), x_reflection=True))
current_mirror_ota_0.add(gdstk.Label('ID', (12.9,7.98), layer=69, texttype=5))
current_mirror_ota_0.add(gdstk.Label('VOUT', (18.49,23.52), layer=69, texttype=5))
current_mirror_ota_0.add(gdstk.Label('VINN', (19.78,5.88), layer=69, texttype=5))
current_mirror_ota_0.add(gdstk.Label('VINP', (9.46,5.88), layer=69, texttype=5))
current_mirror_ota_0.add(gdstk.Label('VSS', (11.84,13.23), layer=71, texttype=5))
current_mirror_ota_0.add(gdstk.Label('VSS', (11.84,13.23), layer=71, texttype=5))
current_mirror_ota_0.add(gdstk.Label('VSS', (11.61,26.25), layer=69, texttype=5))
current_mirror_ota_0.add(gdstk.Label('VSS', (11.84,13.23), layer=71, texttype=5))
current_mirror_ota_0.add(gdstk.Label('VSS', (11.84,13.23), layer=71, texttype=5))
current_mirror_ota_0.add(gdstk.Label('VSS', (11.84,13.23), layer=71, texttype=5))
current_mirror_ota_0.add(gdstk.Label('VSS', (11.84,13.23), layer=71, texttype=5))
current_mirror_ota_0.add(gdstk.Label('VSS', (11.84,13.23), layer=71, texttype=5))
current_mirror_ota_0.add(gdstk.Label('VSS', (11.84,13.23), layer=71, texttype=5))
current_mirror_ota_0.add(gdstk.Label('VSS', (11.84,13.23), layer=71, texttype=5))
current_mirror_ota_0.add(gdstk.Label('VSS', (11.84,13.23), layer=71, texttype=5))
current_mirror_ota_0.add(gdstk.Label('VSS', (11.84,13.23), layer=71, texttype=5))
current_mirror_ota_0.add(gdstk.Label('VSS', (11.84,13.23), layer=71, texttype=5))
current_mirror_ota_0.add(gdstk.Label('VSS', (11.84,13.23), layer=71, texttype=5))
current_mirror_ota_0.add(gdstk.Label('VSS', (11.84,13.23), layer=71, texttype=5))
current_mirror_ota_0.add(gdstk.Label('VSS', (11.84,13.23), layer=71, texttype=5))
current_mirror_ota_0.add(gdstk.Label('VSS', (11.84,13.23), layer=71, texttype=5))
current_mirror_ota_0.add(gdstk.Label('VSS', (11.84,13.23), layer=71, texttype=5))
current_mirror_ota_0.add(gdstk.Label('VSS', (11.84,13.23), layer=71, texttype=5))
current_mirror_ota_0.add(gdstk.Label('VDD', (24.51,0.63), layer=69, texttype=5))
current_mirror_ota_0.add(gdstk.Label('VDD', (23.68,13.23), layer=71, texttype=5))
current_mirror_ota_0.add(gdstk.Label('VDD', (23.68,13.23), layer=71, texttype=5))
current_mirror_ota_0.add(gdstk.Label('VDD', (23.68,13.23), layer=71, texttype=5))
current_mirror_ota_0.add(gdstk.Label('VDD', (23.68,13.23), layer=71, texttype=5))
current_mirror_ota_0.add(gdstk.Label('VDD', (23.68,13.23), layer=71, texttype=5))
current_mirror_ota_0.add(gdstk.Label('VDD', (23.68,13.23), layer=71, texttype=5))
current_mirror_ota_0.add(gdstk.Label('VDD', (23.68,13.23), layer=71, texttype=5))
current_mirror_ota_0.add(gdstk.Label('VDD', (23.68,13.23), layer=71, texttype=5))
current_mirror_ota_0.add(gdstk.Label('VDD', (23.68,13.23), layer=71, texttype=5))
current_mirror_ota_0.add(gdstk.Label('VDD', (23.68,13.23), layer=71, texttype=5))
current_mirror_ota_0.add(gdstk.Label('VDD', (23.68,13.23), layer=71, texttype=5))
current_mirror_ota_0.add(gdstk.Label('VDD', (23.68,13.23), layer=71, texttype=5))

lib.write_gds('CURRENT_MIRROR_OTA_0.gds')
